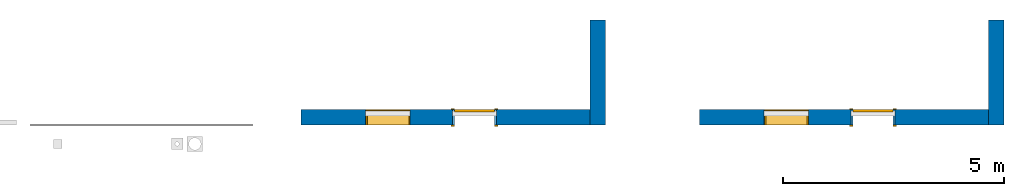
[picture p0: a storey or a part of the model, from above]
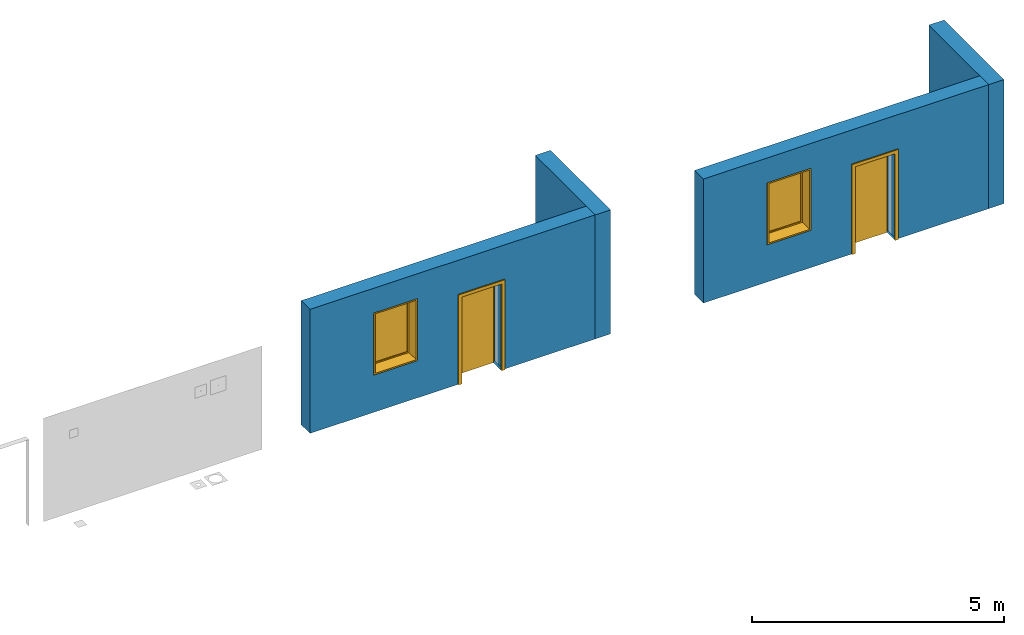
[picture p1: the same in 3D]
Properties of the parts of a building model (IFC2X3), part 1 of 2

# File
Description: ViewDefinition [CoordinationView_V2.0, QuantityTakeOffAddOnView]
File name: Project Number
Time: 2022-03-25T09:45:00
Written by: The EXPRESS Data Manager Version 5.02.0100.07 : 28 Aug 2013
Made in: 20200426_1515(x64) - Exporter 20.2.20.31 - Alternate UI 20.2.20.31
Comment: STEP Physical File produced by: The EXPRESS Data Manager Version 5.02.0100.07 : 28 Aug 2013 * Module: EDMstepFileFactory/EDMstandAlone * Creation date: Fri Mar 25 09:45:00 2022 * Host: DESKTOP-B61V6V9 * Database: C:\Users\3DBYGG~1\AppData\Local\Temp\b66c8e43-4149-422d-8c30-02023fbb521a\7cf2f51e-2db1-4240-b517-61d59570ed5c\ifc * Database version: 5507 * Database creation date: Fri Mar 25 09:44:56 2022 * Schema: IFC2X3 * Model: DataRepository.ifc * Model creation date: Fri Mar 25 09:44:57 2022 * Header model: DataRepository.ifc_HeaderModel * Header model creation date: Fri Mar 25 09:44:57 2022 * EDMuser: sdai-user * EDMgroup: sdai-group * License ID and type: 5605 : Permanent license. Expiry date: * EDMstepFileFactory options: 020000

# IfcProject, Project Number
LongName: Project Name; Phase: Project Status

# IfcSite, Default
RefLatitude: 42, 21, 31, 181945; RefLongitude: -71, -3, -24, -263305; RefElevation: 0 mm
Other - Category: Project Information; Client Name: Owner; Project Address: ## Street City, State Zip; Project Issue Date: Issue Date; Project Name: Project Name; Project Number: Project Number; Project Status: Project Status

# IfcBuilding
Pset_BuildingCommon - NumberOfStoreys: 1
Pset_ProductRequirements - Category: Project Information
Other - Category: Project Information; Client Name: Owner; Project Address: ## Street City, State Zip; Project Issue Date: Issue Date; Project Name: Project Name; Project Number: Project Number; Project Status: Project Status

# IfcBuildingStorey: Level:8mm Head, Level 1
LongName: Level 1; Elevation: 0 mm
Pset_AirSideSystemInformation - Name: Level 1
Pset_ProductRequirements - Name: Level 1; Category: Levels
Constraints - Elevation: 0 mm
Dimensions - Computation Height: 0 mm
Identity Data - Structural: no; Building Story: yes; Name: Level 1
Other - Category: Levels; Family: Level: 8mm Head; Family and Type: Level: 8mm Head; Type: Level: 8mm Head; Type Id: Level: 8mm Head
Constraints(Type) - Elevation Base: Project Base Point
Graphics(Type) - Color: 0; Line Pattern: Center; Line Weight: 1; Symbol: M_Level Head - Circle: M_Level Head - Circle; Symbol at End 1 Default: no; Symbol at End 2 Default: yes
Identity Data(Type) - Type Name: 8mm Head
Other(Type) - Category: Levels; Family Name: Level

# IfcBuildingElementProxy: Door Lining, Dafa_ExFoil_Lining_Foil 2 x double adhesive:Door Lining:279082
In: Level 1
Type - Material: DafaExFoilLiningFoil
Type - Constraints - Default Elevation: 0 mm
Type - Data - Foil Adhesive: DAFA foil adhesive; Vapor Barrier Tape: DAFA Hi-tack vapor barrier tape
Type - Dimensions - Thickness: 1 mm
Type - General - Revision: 1.0
Type - Green Building Properties - DGNB: Coming soon; EDP: Coming soon; EmiCode: Coming soon; Nordic Ecolabel: DAFA ExFoil lining foil is listed in the database for building products that can be used in Nordic Swan Ecolabelled buildings.
Type - Identity Data - Copyright: DAFA Building Solutions A/S; Description: With DAFA ExFoil lining foil, you are ensured an easy and secure installation of a vapor barrier at all 4 sides of openings/windows. This type of DAFA ExFoil lining foil is especially suitable for installation on new or existing vapor barriers, using two pre-installed sheets of double-sided tape.; Manufacturer: DAFA; Model: 250/410 mm x 50 m with 2 x double adhesive; Type Name: Door Lining; URL: https://DAFA-build.com/
Type - Other - Category: Generic Models; NominalWidth: 0 mm; AccessibilityPerformance: n/a; AssetIdentifier: n/a; AssetType: n/a; Author: DAFA Building Solutions A/S; BarCode: n/a; CodePerformance: n/a; Color: Transparent white w/ Lime green text; Constituents: n/a; DurationUnit: Year; ExpectedLife: n/a; Family Name: Dafa_ExFoil_Lining_Foil 2 x double adhesive; Features: Seals the opening all the way around, in one piece. DAFA ExFoil lining foil is fitted with butyl rubber and tape, which significantly facilitates the workflow; Finish: Nonwowen multilayer structure with reinforcing mesh; Grade: n/a; InstallationDate: To be filled by contractor; ManufacturerURL: https://DAFA-build.com; Material: Nonwowen multilayer structure with reinforcing mesh; ModelNumber: 620036876/620036582; ModelReference: DAFA AirStop System; NBSReference: n/a; NominalLength: 50000 mm; ProductInformation: https://DAFA-build.com/en/products/airstop/DAFA-exfoil-lining-foil; Reference: n/a; ReplacementCost: n/a; SerialNumber: n/a; Shape: Rectangular; Size: 250/410 mm x 50 m; TagNumber: n/a; WarrantyDescription: Depends on country.; WarrantyDurationLabor: To be filled by contractor; WarrantyDurationParts: Depends on country. Up to 30 years; WarrantyDurationUnit: Depends on country; WarrantyGuarantorLabor: To be filled by contractor; WarrantyGuarantorParts: To be filled by contractor; WarrantyStartDate: To be filled by contractor
Type - Pset_BuildingElementProxyCommon - Reference: n/a
Type - Pset_ElementShading - Color: Transparent white w/ Lime green text
Type - Pset_ManufacturerOccurrence - BarCode: n/a; SerialNumber: n/a
Type - Pset_ManufacturerTypeInformation - ModelReference: DAFA AirStop System; Manufacturer: DAFA
Type - Pset_PrecastConcreteElementGeneral - SerialNumber: n/a
Type - Pset_ProductRequirements - Category: Generic Models
Type - Pset_QuantityTakeOff - Reference: n/a
Pset_BuildingElementProxyCommon - sets with these values: 2
Constraints - Level: Level: Level 1; Elevation from Level: 0 mm; Moves With Nearby Elements: no; Offset from Host: 0 mm; Host: Level : Level 1
Dimensions - Area: 0.689456 m2; Depth: 120 mm; Height: 2100 mm; Volume: 0.00059376 m3; Width: 750 mm
Graphics - BottomOn: no
Materials and Finishes - ExFoilLining: DafaExFoilLiningFoil
Other - Family: Dafa_ExFoil_Lining_Foil 2 x double adhesive: Door Lining; Family and Type: Dafa_ExFoil_Lining_Foil 2 x double adhesive: Door Lining; Type: Dafa_ExFoil_Lining_Foil 2 x double adhesive: Door Lining; Type Id: Dafa_ExFoil_Lining_Foil 2 x double adhesive: Door Lining
Phasing - Phase Created: New Construction

# IfcBuildingElementProxy: Door Lining, Dafa_ExFoil_Lining_Foil double adhesive and butyl rubber:Door Lining:297118
In: Level 1
Type - Material: DafaExFoilLiningFoil
Type - Constraints - Default Elevation: 0 mm
Type - Data - Foil Adhesive: DAFA foil adhesive; Vapor Barrier Tape: DAFA Hi-tack vapor barrier tape
Type - Dimensions - Thickness: 1 mm
Type - General - Revision: 1.0
Type - Green Building Properties - DGNB: Coming soon; EDP: Coming soon; EmiCode: Coming soon; Nordic Ecolabel: DAFA ExFoil lining foil is listed in the database for building products that can be used in Nordic Swan Ecolabelled buildings.
Type - Identity Data - Copyright: DAFA Building Solutions A/S; Description: With DAFA ExFoil lining foil, you are ensured an easy and secure installation of a vapor barrier at all 4 sides of openings/windows. This type of DAFA ExFoil lining foil is preassembled with butyl rubber and tape, so that it works with rough surfaces such as concrete elements, aerated concrete and wood. Butyl rubber is extra strong and ensures good adhesion.; Manufacturer: DAFA; Model: 200/300/400 mm x 50 m with double adhesive and butyl; Type Name: Door Lining; URL: https://DAFA-build.com/
Type - Other - Category: Generic Models; NominalWidth: 0 mm; AccessibilityPerformance: n/a; AssetIdentifier: n/a; AssetType: n/a; Author: DAFA Building Solutions A/S; BarCode: n/a; CodePerformance: n/a; Color: Transparent white w/ Lime green text; Constituents: n/a; DurationUnit: Year; ExpectedLife: n/a; Family Name: Dafa_ExFoil_Lining_Foil double adhesive and butyl rubber; Features: Seals the opening all the way around, in one piece. DAFA ExFoil lining foil is fitted with butyl rubber and tape, which significantly facilitates the workflow; Finish: Nonwowen multilayer structure with reinforcing mesh; Grade: n/a; InstallationDate: To be filled by contractor; ManufacturerURL: https://DAFA-build.com; Material: Nonwowen multilayer structure with reinforcing mesh; ModelNumber: 620036874/620036875/620036584; ModelReference: DAFA AirStop System; NBSReference: n/a; NominalLength: 50000 mm; ProductInformation: https://DAFA-build.com/en/products/airstop/DAFA-exfoil-lining-foil; Reference: n/a; ReplacementCost: n/a; SerialNumber: n/a; Shape: Rectangular; Size: 200/300/400 mm x 50 m; TagNumber: n/a; WarrantyDescription: Depends on country.; WarrantyDurationLabor: To be filled by contractor; WarrantyDurationParts: Depends on country. Up to 30 years; WarrantyDurationUnit: Depends on country; WarrantyGuarantorLabor: To be filled by contractor; WarrantyGuarantorParts: To be filled by contractor; WarrantyStartDate: To be filled by contractor
Type - Pset_BuildingElementProxyCommon - Reference: n/a
Type - Pset_ElementShading - Color: Transparent white w/ Lime green text
Type - Pset_ManufacturerOccurrence - BarCode: n/a; SerialNumber: n/a
Type - Pset_ManufacturerTypeInformation - ModelReference: DAFA AirStop System; Manufacturer: DAFA
Type - Pset_PrecastConcreteElementGeneral - SerialNumber: n/a
Type - Pset_ProductRequirements - Category: Generic Models
Type - Pset_QuantityTakeOff - Reference: n/a
Pset_BuildingElementProxyCommon - sets with these values: 2
Constraints - Level: Level: Level 1; Elevation from Level: 0 mm; Moves With Nearby Elements: no; Offset from Host: 0 mm; Host: Level : Level 1
Dimensions - Area: 0.689456 m2; Depth: 120 mm; Height: 2100 mm; Volume: 0.00059376 m3; Width: 750 mm
Graphics - BottomOn: no
Materials and Finishes - ExFoilLining: DafaExFoilLiningFoil
Other - Family: Dafa_ExFoil_Lining_Foil double adhesive and butyl rubber: Door Lining; Family and Type: Dafa_ExFoil_Lining_Foil double adhesive and butyl rubber: Door Lining; Type: Dafa_ExFoil_Lining_Foil double adhesive and butyl rubber: Door Lining; Type Id: Dafa_ExFoil_Lining_Foil double adhesive and butyl rubber: Door Lining
Phasing - Phase Created: New Construction

# IfcBuildingElementProxy: Door Lining, Dafa_ExFoil_Lining_Foil 2 x double adhesive-WallBased:Door Lining:248374
In: Level 1
Type - Material: DafaExFoilLiningFoil
Type - Constraints(Type) - Default Elevation: 0 mm
Type - Data(Type) - Foil Adhesive: DAFA foil adhesive; Vapor Barrier Tape: DAFA Hi-tack vapor barrier tape
Type - Dimensions(Type) - Area: 0.624 m2; Depth: 120 mm; Height: 2100 mm; Width: 1000 mm
Type - General(Type) - Revision: 1.0
Type - Graphics(Type) - BottomOn: no
Type - Green Building Properties(Type) - DGNB: Coming soon; EDP: Coming soon; EmiCode: Coming soon; Nordic Ecolabel: DAFA ExFoil lining foil is listed in the database for building products that can be used in Nordic Swan Ecolabelled buildings.
Type - Identity Data(Type) - Copyright: DAFA Building Solutions A/S; Description: With DAFA ExFoil lining foil, you are ensured an easy and secure installation of a vapor barrier at all 4 sides of openings/windows. This type of DAFA ExFoil lining foil is especially suitable for installation on new or existing vapor barriers, using two pre-installed sheets of double-sided tape.; Manufacturer: DAFA; Model: 250/410 mm x 50 m with 2 x double adhesive; Type Name: Door Lining; URL: https://DAFA-build.com/
Type - Other(Type) - Category: Generic Models; NominalWidth: 0 mm; AccessibilityPerformance: n/a; AssetIdentifier: n/a; AssetType: n/a; Author: DAFA Building Solutions A/S; BarCode: n/a; CodePerformance: n/a; Color: Transparent white w/ Lime green text; Constituents: n/a; DurationUnit: Year; ExpectedLife: n/a; Family Name: Dafa_ExFoil_Lining_Foil 2 x double adhesive-WallBased; Features: Seals the opening all the way around, in one piece. DAFA ExFoil lining foil is fitted with butyl rubber and tape, which significantly facilitates the workflow; Finish: Nonwowen multilayer structure with reinforcing mesh; Grade: n/a; InstallationDate: To be filled by contractor; ManufacturerURL: https://DAFA-build.com; Material: Nonwowen multilayer structure with reinforcing mesh; ModelNumber: 620036876/620036582; ModelReference: DAFA AirStop System; NBSReference: n/a; NominalLength: 50000 mm; ProductInformation: https://DAFA-build.com/en/products/airstop/DAFA-exfoil-lining-foil; Reference: n/a; ReplacementCost: n/a; SerialNumber: n/a; Shape: Rectangular; Size: 250/410 mm x 50 m; TagNumber: n/a; WarrantyDescription: Depends on country.; WarrantyDurationLabor: To be filled by contractor; WarrantyDurationParts: Depends on country. Up to 30 years; WarrantyDurationUnit: Depends on country; WarrantyGuarantorLabor: To be filled by contractor; WarrantyGuarantorParts: To be filled by contractor; WarrantyStartDate: To be filled by contractor
Type - Pset_BuildingElementProxyCommon - Reference: n/a
Type - Pset_ElementShading - Color: Transparent white w/ Lime green text
Type - Pset_ManufacturerOccurrence - BarCode: n/a; SerialNumber: n/a
Type - Pset_ManufacturerTypeInformation - ModelReference: DAFA AirStop System; Manufacturer: DAFA
Type - Pset_PrecastConcreteElementGeneral - SerialNumber: n/a
Type - Pset_ProductRequirements - Category: Generic Models
Type - Pset_QuantityTakeOff - Reference: n/a
Pset_BuildingElementProxyCommon - sets with these values: 2
Constraints - Level: Level: Level 1; Elevation from Level: 0.708015 mm
Dimensions - Area: 0.749956 m2; OffsetInWall: 25 mm; Volume: 0.00062376 m3
Other - Category: Generic Models; Host Id: Basic Wall: Exterior - Brick on Mtl. Stud; Family: Dafa_ExFoil_Lining_Foil 2 x double adhesive-WallBased: Door Lining; Family and Type: Dafa_ExFoil_Lining_Foil 2 x double adhesive-WallBased: Door Lining; Type: Dafa_ExFoil_Lining_Foil 2 x double adhesive-WallBased: Door Lining; Type Id: Dafa_ExFoil_Lining_Foil 2 x double adhesive-WallBased: Door Lining
Phasing - Phase Created: New Construction

# IfcBuildingElementProxy: Door Lining, Dafa_ExFoil_Lining_Foil double adhesive and butyl rubber-WallBased:Door Lining:297191
In: Level 1
Type - Material: DafaExFoilLiningFoil
Type - Constraints(Type) - Default Elevation: 0 mm
Type - Data(Type) - Foil Adhesive: DAFA foil adhesive; Vapor Barrier Tape: DAFA Hi-tack vapor barrier tape
Type - Dimensions(Type) - Area: 0.624 m2; Depth: 120 mm; Height: 2100 mm; Width: 1000 mm
Type - General(Type) - Revision: 1.0
Type - Graphics(Type) - BottomOn: no
Type - Green Building Properties(Type) - DGNB: Coming soon; EDP: Coming soon; EmiCode: Coming soon; Nordic Ecolabel: DAFA ExFoil lining foil is listed in the database for building products that can be used in Nordic Swan Ecolabelled buildings.
Type - Identity Data(Type) - Copyright: DAFA Building Solutions A/S; Description: With DAFA ExFoil lining foil, you are ensured an easy and secure installation of a vapor barrier at all 4 sides of openings/windows. This type of DAFA ExFoil lining foil is preassembled with butyl rubber and tape, so that it works with rough surfaces such as concrete elements, aerated concrete and wood. Butyl rubber is extra strong and ensures good adhesion.; Manufacturer: DAFA; Model: 200/300/400 mm x 50 m with double adhesive and butyl; Type Name: Door Lining; URL: https://DAFA-build.com/
Type - Other(Type) - Category: Generic Models; NominalWidth: 0 mm; AccessibilityPerformance: n/a; AssetIdentifier: n/a; AssetType: n/a; Author: DAFA Building Solutions A/S; BarCode: n/a; CodePerformance: n/a; Color: Transparent white w/ Lime green text; Constituents: n/a; DurationUnit: Year; ExpectedLife: n/a; Family Name: Dafa_ExFoil_Lining_Foil double adhesive and butyl rubber-WallBased; Features: Seals the opening all the way around, in one piece. DAFA ExFoil lining foil is fitted with butyl rubber and tape, which significantly facilitates the workflow; Finish: Nonwowen multilayer structure with reinforcing mesh; Grade: n/a; InstallationDate: To be filled by contractor; ManufacturerURL: https://DAFA-build.com; Material: Nonwowen multilayer structure with reinforcing mesh; ModelNumber: 620036874/620036875/620036584; ModelReference: DAFA AirStop System; NBSReference: n/a; NominalLength: 50000 mm; ProductInformation: https://DAFA-build.com/en/products/airstop/DAFA-exfoil-lining-foil; Reference: n/a; ReplacementCost: n/a; SerialNumber: n/a; Shape: Rectangular; Size: 200/300/400 mm x 50 m; TagNumber: n/a; WarrantyDescription: Depends on country.; WarrantyDurationLabor: To be filled by contractor; WarrantyDurationParts: Depends on country. Up to 30 years; WarrantyDurationUnit: Depends on country; WarrantyGuarantorLabor: To be filled by contractor; WarrantyGuarantorParts: To be filled by contractor; WarrantyStartDate: To be filled by contractor
Type - Pset_BuildingElementProxyCommon - Reference: n/a
Type - Pset_ElementShading - Color: Transparent white w/ Lime green text
Type - Pset_ManufacturerOccurrence - BarCode: n/a; SerialNumber: n/a
Type - Pset_ManufacturerTypeInformation - ModelReference: DAFA AirStop System; Manufacturer: DAFA
Type - Pset_PrecastConcreteElementGeneral - SerialNumber: n/a
Type - Pset_ProductRequirements - Category: Generic Models
Type - Pset_QuantityTakeOff - Reference: n/a
Pset_BuildingElementProxyCommon - sets with these values: 2
Constraints - Level: Level: Level 1; Elevation from Level: 0.708015 mm
Dimensions - Area: 0.749956 m2; OffsetInWall: 25 mm; Volume: 0.00062376 m3
Other - Category: Generic Models; Host Id: Basic Wall: Exterior - Brick on Mtl. Stud; Family: Dafa_ExFoil_Lining_Foil double adhesive and butyl rubber-WallBased: Door Lining; Family and Type: Dafa_ExFoil_Lining_Foil double adhesive and butyl rubber-WallBased: Door Lining; Type: Dafa_ExFoil_Lining_Foil double adhesive and butyl rubber-WallBased: Door Lining; Type Id: Dafa_ExFoil_Lining_Foil double adhesive and butyl rubber-WallBased: Door Lining
Phasing - Phase Created: New Construction

# IfcBuildingElementProxy: Standard, Dafa_ExFoil:Standard:239079
In: Level 1
Type - Material: DafaExFoil
Type - Constraints - Default Elevation: 0 mm
Type - Data - Foil Adhesive: DAFA foil adhesive; Vapor Barrier Tape: DAFA Hi-tack vapor barrier tape
Type - General - Revision: 1.0
Type - Green Building Properties - DGNB: Coming soon; EDP: Coming soon; EmiCode: Coming soon; Nordic Ecolabel: DAFA ExFoil is listed in the database for building products that can be used in Nordic Swan Ecolabelled buildings.
Type - Identity Data - Copyright: DAFA Building Solutions A/S; Description: DAFA ExFoil vapor barrier foil is an extra strong foil vapor barrier with reinforcing mesh and a multilayer structure which makes it extremely stretch and tear-resistant.; Manufacturer: DAFA; Model: ExFoil; Type Name: Standard; URL: https://DAFA-build.com/
Type - Other - Category: Generic Models; NominalWidth: 0 mm; AccessibilityPerformance: n/a; AssetIdentifier: n/a; AssetType: n/a; Author: DAFA Building Solutions A/S; BarCode: n/a; CodePerformance: n/a; Color: Transparent white w/ Lime green text; Constituents: n/a; DurationUnit: Year; ExpectedLife: n/a; Family Name: Dafa_ExFoil; Features: Far more construction-friendly than a standard PE vapor barrier, making installation easier. With reinforcing mesh, DAFA ExFoil is much stronger than a PE vapor barrier; Finish: Multilayer structure with mesh reinforcement; Grade: n/a; InstallationDate: To be filled by contractor; ManufacturerURL: https://DAFA-build.com; Material: Nonwowen multilayer structure with reinforcing mesh; ModelNumber: 620035141 / 620038158; ModelReference: DAFA AirStop System; NBSReference: n/a; NominalLength: 0 mm; ProductInformation: https://dafa-build.com/en/products/airstop/exfoil; Reference: n/a; ReplacementCost: n/a; SerialNumber: n/a; Shape: Rectangular/roll; Size: 2,15 x 46, 5 m / 2,7 x 37 m; TagNumber: n/a; WarrantyDescription: Depends on country.; WarrantyDurationLabor: To be filled by contractor; WarrantyDurationParts: Depends on country. 30 years; WarrantyDurationUnit: Depends on country; WarrantyGuarantorLabor: To be filled by contractor; WarrantyGuarantorParts: To be filled by contractor; WarrantyStartDate: To be filled by contractor
Type - Pset_BuildingElementProxyCommon - Reference: n/a
Type - Pset_ElementShading - Color: Transparent white w/ Lime green text
Type - Pset_ManufacturerOccurrence - BarCode: n/a; SerialNumber: n/a
Type - Pset_ManufacturerTypeInformation - ModelReference: DAFA AirStop System; Manufacturer: DAFA
Type - Pset_PrecastConcreteElementGeneral - SerialNumber: n/a
Type - Pset_ProductRequirements - Category: Generic Models
Type - Pset_QuantityTakeOff - Reference: n/a
Pset_BuildingElementProxyCommon - sets with these values: 2
Constraints - Level: Level: Level 1; Elevation from Level: 0 mm; Host: Level : Level 1; Moves With Nearby Elements: no; Offset from Host: 0 mm
Dimensions - Area: 12.5075 m2; Height: 2500 mm; Thickness: 1 mm; Volume: 0.0125 m3; Width: 5000 mm
Materials and Finishes - ExFoil: DafaExFoil
Other - Family: Dafa_ExFoil: Standard; Family and Type: Dafa_ExFoil: Standard; Type: Dafa_ExFoil: Standard; Type Id: Dafa_ExFoil: Standard
Phasing - Phase Created: New Construction

# IfcBuildingElementProxy: Type 195, Dafa_Hi-tack_Cable_Collar:Type 195:256911
In: Level 1
Type - Material: DAFA Hitack
Type - Constraints - Default Elevation: 0 mm
Type - General - Revision: 1.0
Type - Green Building Properties - DGNB: Coming soon; EDP: Coming soon; EmiCode: Coming soon; Nordic Ecolabel: DAFA Hi-tack cable collar is listed in the database for building products that can be used in Nordic Swan Ecolabelled buildings
Type - Identity Data - Copyright: DAFA Building Solutions A/S; Description: DAFA Hi-tack universal cable collars are a patented solution used for sealing the vapor barrier around cable and ceiling outlet penetrations. Attach the collar directly to the vapor barrier – quickly, simply and securely. A single flexible gasket for all common pipe dimensions/exhaust ducts; Manufacturer: DAFA; Model: Type 195; Type Name: Type 195; URL: https://DAFA-build.com/
Type - Other - Category: Generic Models; AccessibilityPerformance: n/a; AssetIdentifier: n/a; AssetType: n/a; Author: DAFA Building Solutions A/S; BarCode: n/a; CodePerformance: n/a; Color: Black; Constituents: n/a; DurationUnit: Year; ExpectedLife: n/a; Family Name: Dafa_Hi-tack_Cable_Collar; Features: A single flexible gasket for all common cable dimensions.Can be used for both cables and ceiling outlets (PL junction boxes with rubber plugs). Simple, fast and secure installation. No special tools required. Installed without the need for subsequent sealing, gluing, caulking, etc.; Finish: The product is made from a black, soft and flexible EPDM fabric, coated with a strong acrylic adhesive. The adhesive has been specially developed for sealing and laminating a DAFA HiFoil and ExFoil vapour barriers. The 1.2 mm thick EPDM fabric is supplied with pre-punched markings.; Grade: n/a; InstallationDate: To be filled by contractor; ManufacturerURL: https://DAFA-build.com; Material: EPDM; ModelNumber: 620026738; ModelReference: DAFA AirStop System; NBSReference: n/a; NominalLength: 195 mm; NominalWidth: 195 mm; ProductInformation: https://dafa-build.com/en/products/airstop/dafa-hi-tack-universal-cable-collar; Reference: n/a; ReplacementCost: n/a; SerialNumber: n/a; Shape: Rectangular; Size: 195 x 195 mm; TagNumber: n/a; WarrantyDescription: Depends on country.; WarrantyDurationLabor: To be filled by contractor; WarrantyDurationParts: Depends on country. Up to 30 years; WarrantyDurationUnit: Depends on country; WarrantyGuarantorLabor: To be filled by contractor; WarrantyGuarantorParts: To be filled by contractor; WarrantyStartDate: To be filled by contractor
Type - Pset_BuildingElementProxyCommon - Reference: n/a
Type - Pset_ElementShading - Color: Black
Type - Pset_ManufacturerOccurrence - BarCode: n/a; SerialNumber: n/a
Type - Pset_ManufacturerTypeInformation - ModelReference: DAFA AirStop System; Manufacturer: DAFA
Type - Pset_PrecastConcreteElementGeneral - SerialNumber: n/a
Type - Pset_ProductRequirements - Category: Generic Models
Type - Pset_QuantityTakeOff - Reference: n/a
Pset_BuildingElementProxyCommon - sets with these values: 2
Constraints - Level: Level: Level 1; Elevation from Level: 0 mm; Moves With Nearby Elements: no; Offset from Host: 0 mm; Host: Level : Level 1
Dimensions - Area: 0.038493 m2; Volume: 0.00004563 m3; Width: 195 mm
Materials and Finishes - Collar: DAFA Collar; Hitack: DAFA Hitack
Other - Family: Dafa_Hi-tack_Cable_Collar: Type 195; Family and Type: Dafa_Hi-tack_Cable_Collar: Type 195; Type: Dafa_Hi-tack_Cable_Collar: Type 195; Type Id: Dafa_Hi-tack_Cable_Collar: Type 195
Phasing - Phase Created: New Construction

# IfcBuildingElementProxy: Type 195, Dafa_Hi-tack_Cable_Collar_FaceBased:Type 195:278831
In: Level 1
Type - Material: DAFA Hitack
Type - Constraints - Default Elevation: 1219.2 mm
Type - Dimensions - Width: 195 mm
Type - General - Revision: 1.0
Type - Green Building Properties - DGNB: Coming soon; EDP: Coming soon; EmiCode: Coming soon; Nordic Ecolabel: DAFA Hi-tack cable collar is listed in the database for building products that can be used in Nordic Swan Ecolabelled buildings
Type - Identity Data - Copyright: DAFA Building Solutions A/S; Description: DAFA Hi-tack universal cable collars are a patented solution used for sealing the vapor barrier around cable and ceiling outlet penetrations. Attach the collar directly to the vapor barrier – quickly, simply and securely. A single flexible gasket for all common pipe dimensions/exhaust ducts; Manufacturer: DAFA; Model: Type 195; Type Name: Type 195; URL: https://DAFA-build.com/
Type - Materials and Finishes - Hitack: DAFA Hitack
Type - Other - Category: Generic Models; AccessibilityPerformance: n/a; AssetIdentifier: n/a; AssetType: n/a; Author: DAFA Building Solutions A/S; BarCode: n/a; CodePerformance: n/a; Color: Black; Constituents: n/a; DurationUnit: Year; ExpectedLife: n/a; Family Name: Dafa_Hi-tack_Cable_Collar_FaceBased; Features: A single flexible gasket for all common cable dimensions.Can be used for both cables and ceiling outlets (PL junction boxes with rubber plugs). Simple, fast and secure installation. No special tools required. Installed without the need for subsequent sealing, gluing, caulking, etc.; Finish: The product is made from a black, soft and flexible EPDM fabric, coated with a strong acrylic adhesive. The adhesive has been specially developed for sealing and laminating a DAFA HiFoil and ExFoil vapour barriers. The 1.2 mm thick EPDM fabric is supplied with pre-punched markings.; Grade: n/a; InstallationDate: To be filled by contractor; ManufacturerURL: https://DAFA-build.com; Material: EPDM; ModelNumber: 620026738; ModelReference: DAFA AirStop System; NBSReference: n/a; NominalLength: 195 mm; NominalWidth: 195 mm; ProductInformation: https://dafa-build.com/en/products/airstop/dafa-hi-tack-universal-cable-collar; Reference: n/a; ReplacementCost: n/a; SerialNumber: n/a; Shape: Rectangular; Size: 195 x 195 mm; TagNumber: n/a; WarrantyDescription: Depends on country.; WarrantyDurationLabor: To be filled by contractor; WarrantyDurationParts: Depends on country. Up to 30 years; WarrantyDurationUnit: Depends on country; WarrantyGuarantorLabor: To be filled by contractor; WarrantyGuarantorParts: To be filled by contractor; WarrantyStartDate: To be filled by contractor
Type - Pset_BuildingElementProxyCommon - Reference: n/a
Type - Pset_ElementShading - Color: Black
Type - Pset_ManufacturerOccurrence - BarCode: n/a; SerialNumber: n/a
Type - Pset_ManufacturerTypeInformation - ModelReference: DAFA AirStop System; Manufacturer: DAFA
Type - Pset_PrecastConcreteElementGeneral - SerialNumber: n/a
Type - Pset_ProductRequirements - Category: Generic Models
Type - Pset_QuantityTakeOff - Reference: n/a
Pset_BuildingElementProxyCommon - sets with these values: 2
Constraints - Level: Level: Level 1; Schedule Level: Level: Level 1; Elevation from Level: 1900 mm; Host: Dafa_ExFoil : Standard
Dimensions - Area: 0.038493 m2; Volume: 0.00004563 m3
Materials and Finishes - Collar: DAFA Collar
Other - Family: Dafa_Hi-tack_Cable_Collar_FaceBased: Type 195; Family and Type: Dafa_Hi-tack_Cable_Collar_FaceBased: Type 195; Type: Dafa_Hi-tack_Cable_Collar_FaceBased: Type 195; Type Id: Dafa_Hi-tack_Cable_Collar_FaceBased: Type 195
Phasing - Phase Created: New Construction

# IfcBuildingElementProxy: Type 260, Dafa_Hi-tack_Pipe_Collar:Type 260:253812
In: Level 1
Type - Material: DAFA Hitack
Type - Constraints - Default Elevation: 0 mm
Type - Construction - HoleType: 1
Type - Dimensions - Width: 260 mm
Type - General - Revision: 1.0; Type 260: yes; Type 345: no
Type - Graphics - FilledHole: no
Type - Green Building Properties - DGNB: Coming soon; EDP: Coming soon; EmiCode: Coming soon; Nordic Ecolabel: The DAFA Hi-tack pipe collar is included in the Nordic Ecolabellings database of construction products that can be used in Swan-labelled buildings.
Type - Identity Data - Copyright: DAFA Building Solutions A/S; Description: DAFA Hi-tack universal pipe collars are a patented solution used for sealing the vapor barrier around pipe penetrations. Attach the collar directly to the vapor barrier – quickly, simply and securely.; Manufacturer: DAFA; Model: Type 260; Type Name: Type 260; URL: https://DAFA-build.com/
Type - Other - Category: Generic Models; AccessibilityPerformance: n/a; AssetIdentifier: n/a; AssetType: n/a; Author: DAFA Building Solutions A/S; BarCode: n/a; CodePerformance: n/a; Color: Black; Constituents: n/a; DurationUnit: Year; ExpectedLife: n/a; Family Name: Dafa_Hi-tack_Pipe_Collar; Features: A single flexible seal suitable for all common pipe dimensions/ventilations shafts (but not flexible pipe). Simple, fast and secure installation. No special tools required. Installed without the need for subsequent sealing, gluing, caulking, etc.; Finish: The product is made from a black, soft and flexible EPDM fabric, coated with a strong acrylic adhesive. The adhesive has been specially developed for sealing and laminating a DAFA HiFoil and ExFoil vapour barriers. The 1.2 mm thick EPDM fabric is supplied with pre-punched markings.; Grade: n/a; InstallationDate: To be filled by contractor; ManufacturerURL: https://DAFA-build.com; Material: EPDM; ModelNumber: 620026737; ModelReference: DAFA AirStop System; NBSReference: n/a; NominalLength: 260 mm; NominalWidth: 260 mm; ProductInformation: https://dafa-build.com/en/products/airstop/dafa-hi-tack-pipe-collar; Reference: n/a; ReplacementCost: n/a; SerialNumber: n/a; Shape: Rectangular; Size: 260 x 260 mm; TagNumber: n/a; WarrantyDescription: Depends on country.; WarrantyDurationLabor: To be filled by contractor; WarrantyDurationParts: Depends on country. Up to 30 years; WarrantyDurationUnit: Depends on country; WarrantyGuarantorLabor: To be filled by contractor; WarrantyGuarantorParts: To be filled by contractor; WarrantyStartDate: To be filled by contractor
Type - Pset_BuildingElementProxyCommon - Reference: n/a
Type - Pset_ElementShading - Color: Black
Type - Pset_ManufacturerOccurrence - BarCode: n/a; SerialNumber: n/a
Type - Pset_ManufacturerTypeInformation - ModelReference: DAFA AirStop System; Manufacturer: DAFA
Type - Pset_PrecastConcreteElementGeneral - SerialNumber: n/a
Type - Pset_ProductRequirements - Category: Generic Models
Type - Pset_QuantityTakeOff - Reference: n/a
Pset_BuildingElementProxyCommon - sets with these values: 2
Constraints - Level: Level: Level 1; Elevation from Level: 0 mm; Moves With Nearby Elements: no; Offset from Host: 0 mm; Host: Level : Level 1
Construction - Circle: 3
Dimensions - Area: 0.0685633 m2; Radius: 45 mm; Volume: 0.0000734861 m3
General - 100mmCircle: no; 12mmCircle: no; 135mmCircle: no; 25mmCircle: no; 45mmCircle: yes; 55mmCircle: no; 60mmCircle: no; 70mmCircle: no; CableCollar: no
Materials and Finishes - Collar: DAFA Collar; Hitack: DAFA Hitack
Other - Family: Dafa_Hi-tack_Pipe_Collar: Type 260; Family and Type: Dafa_Hi-tack_Pipe_Collar: Type 260; Type: Dafa_Hi-tack_Pipe_Collar: Type 260; Type Id: Dafa_Hi-tack_Pipe_Collar: Type 260
Phasing - Phase Created: New Construction

# IfcBuildingElementProxy: Type 260, Dafa_Hi-tack_Pipe_Collar_FaceBased:Type 260:277890
In: Level 1
Type - Material: DAFA Hitack
Type - Constraints - Default Elevation: 1219.2 mm
Type - Construction - HoleType: 1
Type - Data - Circle: 3
Type - General - Revision: 1.0
Type - Graphics - FilledHole: no
Type - Green Building Properties - DGNB: Coming soon; EDP: Coming soon; EmiCode: Coming soon; Nordic Ecolabel: The DAFA Hi-tack pipe collar is included in the Nordic Ecolabellings database of construction products that can be used in Swan-labelled buildings.
Type - Identity Data - Copyright: DAFA Building Solutions A/S; Description: DAFA Hi-tack universal pipe collars are a patented solution used for sealing the vapor barrier around pipe penetrations. Attach the collar directly to the vapor barrier – quickly, simply and securely.; Manufacturer: DAFA; Model: Type 260; Type Name: Type 260; URL: https://DAFA-build.com/
Type - Materials and Finishes - Collar: DAFA Collar; Hitack: DAFA Hitack
Type - Other - Category: Generic Models; AccessibilityPerformance: n/a; AssetIdentifier: n/a; AssetType: n/a; Author: DAFA Building Solutions A/S; BarCode: n/a; CodePerformance: n/a; Color: Black; Constituents: n/a; DurationUnit: Year; ExpectedLife: n/a; Family Name: Dafa_Hi-tack_Pipe_Collar_FaceBased; Features: A single flexible seal suitable for all common pipe dimensions/ventilations shafts (but not flexible pipe). Simple, fast and secure installation. No special tools required. Installed without the need for subsequent sealing, gluing, caulking, etc.; Finish: The product is made from a black, soft and flexible EPDM fabric, coated with a strong acrylic adhesive. The adhesive has been specially developed for sealing and laminating a DAFA HiFoil and ExFoil vapour barriers. The 1.2 mm thick EPDM fabric is supplied with pre-punched markings.; Grade: n/a; InstallationDate: To be filled by contractor; ManufacturerURL: https://DAFA-build.com; Material: EPDM; ModelNumber: 620026737; ModelReference: DAFA AirStop System; NBSReference: n/a; NominalLength: 260 mm; NominalWidth: 260 mm; ProductInformation: https://dafa-build.com/en/products/airstop/dafa-hi-tack-pipe-collar; Reference: n/a; ReplacementCost: n/a; SerialNumber: n/a; Shape: Rectangular; Size: 260 x 260 mm; TagNumber: n/a; WarrantyDescription: Depends on country.; WarrantyDurationLabor: To be filled by contractor; WarrantyDurationParts: Depends on country. Up to 30 years; WarrantyDurationUnit: Depends on country; WarrantyGuarantorLabor: To be filled by contractor; WarrantyGuarantorParts: To be filled by contractor; WarrantyStartDate: To be filled by contractor
Type - Pset_BuildingElementProxyCommon - Reference: n/a
Type - Pset_ElementShading - Color: Black
Type - Pset_ManufacturerOccurrence - BarCode: n/a; SerialNumber: n/a
Type - Pset_ManufacturerTypeInformation - ModelReference: DAFA AirStop System; Manufacturer: DAFA
Type - Pset_PrecastConcreteElementGeneral - SerialNumber: n/a
Type - Pset_ProductRequirements - Category: Generic Models
Type - Pset_QuantityTakeOff - Reference: n/a
Pset_BuildingElementProxyCommon - sets with these values: 2
Constraints - Level: Level: Level 1; Elevation from Level: 1900 mm; Host: Dafa_ExFoil : Standard; Schedule Level: Level: Level 1
Dimensions - Area: 0.0682994 m2; Volume: 0.000080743 m3
Other - Family: Dafa_Hi-tack_Pipe_Collar_FaceBased: Type 260; Family and Type: Dafa_Hi-tack_Pipe_Collar_FaceBased: Type 260; Type: Dafa_Hi-tack_Pipe_Collar_FaceBased: Type 260; Type Id: Dafa_Hi-tack_Pipe_Collar_FaceBased: Type 260
Phasing - Phase Created: New Construction

# IfcBuildingElementProxy: Type 345, Dafa_Hi-tack_Pipe_Collar:Type 345:254169
In: Level 1
Type - Material: DAFA Hitack
Type - Constraints - Default Elevation: 0 mm
Type - Construction - HoleType: 2
Type - Dimensions - Width: 345 mm
Type - General - Revision: 1.0; Type 260: no; Type 345: yes
Type - Graphics - FilledHole: no
Type - Green Building Properties - DGNB: Coming soon; EDP: Coming soon; EmiCode: Coming soon; Nordic Ecolabel: The DAFA Hi-tack pipe collar is included in the Nordic Ecolabellings database of construction products that can be used in Swan-labelled buildings.
Type - Identity Data - Copyright: DAFA Building Solutions A/S; Description: DAFA Hi-tack universal pipe collars are a patented solution used for sealing the vapor barrier around pipe penetrations. Attach the collar directly to the vapor barrier – quickly, simply and securely.; Manufacturer: DAFA; Model: Type 345; Type Name: Type 345; URL: https://DAFA-build.com/
Type - Other - Category: Generic Models; AccessibilityPerformance: n/a; AssetIdentifier: n/a; AssetType: n/a; Author: DAFA Building Solutions A/S; BarCode: n/a; CodePerformance: n/a; Color: Black; Constituents: n/a; DurationUnit: Year; ExpectedLife: n/a; Family Name: Dafa_Hi-tack_Pipe_Collar; Features: A single flexible seal suitable for all common pipe dimensions/ventilations shafts (but not flexible pipe). Simple, fast and secure installation. No special tools required. Installed without the need for subsequent sealing, gluing, caulking, etc.; Finish: The product is made from a black, soft and flexible EPDM fabric, coated with a strong acrylic adhesive. The adhesive has been specially developed for sealing and laminating a DAFA HiFoil and ExFoil vapour barriers. The 1.2 mm thick EPDM fabric is supplied with pre-punched markings.; Grade: n/a; InstallationDate: To be filled by contractor; ManufacturerURL: https://DAFA-build.com; Material: EPDM; ModelNumber: 620027032; ModelReference: DAFA AirStop System; NBSReference: n/a; NominalLength: 345 mm; NominalWidth: 345 mm; ProductInformation: https://dafa-build.com/en/products/airstop/dafa-hi-tack-pipe-collar; Reference: n/a; ReplacementCost: n/a; SerialNumber: n/a; Shape: Rectangular; Size: 345 x 345 mm; TagNumber: n/a; WarrantyDescription: Depends on country.; WarrantyDurationLabor: To be filled by contractor; WarrantyDurationParts: Depends on country. Up to 30 years; WarrantyDurationUnit: Depends on country; WarrantyGuarantorLabor: To be filled by contractor; WarrantyGuarantorParts: To be filled by contractor; WarrantyStartDate: To be filled by contractor
Type - Pset_BuildingElementProxyCommon - Reference: n/a
Type - Pset_ElementShading - Color: Black
Type - Pset_ManufacturerOccurrence - BarCode: n/a; SerialNumber: n/a
Type - Pset_ManufacturerTypeInformation - ModelReference: DAFA AirStop System; Manufacturer: DAFA
Type - Pset_PrecastConcreteElementGeneral - SerialNumber: n/a
Type - Pset_ProductRequirements - Category: Generic Models
Type - Pset_QuantityTakeOff - Reference: n/a
Pset_BuildingElementProxyCommon - sets with these values: 2
Constraints - Level: Level: Level 1; Elevation from Level: 0 mm; Moves With Nearby Elements: no; Offset from Host: 0 mm; Host: Level : Level 1
Construction - Circle: 3
Dimensions - Area: 0.120871 m2; Radius: 135 mm; Volume: 0.0000741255 m3
General - 100mmCircle: no; 12mmCircle: no; 25mmCircle: no; 55mmCircle: no; 60mmCircle: no; 70mmCircle: no; CableCollar: no; 135mmCircle: yes; 45mmCircle: no
Materials and Finishes - Collar: DAFA Collar; Hitack: DAFA Hitack
Other - Family: Dafa_Hi-tack_Pipe_Collar: Type 345; Family and Type: Dafa_Hi-tack_Pipe_Collar: Type 345; Type: Dafa_Hi-tack_Pipe_Collar: Type 345; Type Id: Dafa_Hi-tack_Pipe_Collar: Type 345
Phasing - Phase Created: New Construction

# IfcBuildingElementProxy: Type 345, Dafa_Hi-tack_Pipe_Collar_FaceBased:Type 345:278053
In: Level 1
Type - Material: DAFA Hitack
Type - Constraints - Default Elevation: 1219.2 mm
Type - Construction - HoleType: 2
Type - Data - Circle: 3
Type - General - Revision: 1.0
Type - Graphics - FilledHole: no
Type - Green Building Properties - DGNB: Coming soon; EDP: Coming soon; EmiCode: Coming soon; Nordic Ecolabel: The DAFA Hi-tack pipe collar is included in the Nordic Ecolabellings database of construction products that can be used in Swan-labelled buildings.
Type - Identity Data - Copyright: DAFA Building Solutions A/S; Description: DAFA Hi-tack universal pipe collars are a patented solution used for sealing the vapor barrier around pipe penetrations. Attach the collar directly to the vapor barrier – quickly, simply and securely.; Manufacturer: DAFA; Model: Type 345; Type Name: Type 345; URL: https://DAFA-build.com/
Type - Materials and Finishes - Collar: DAFA Collar; Hitack: DAFA Hitack
Type - Other - Category: Generic Models; AccessibilityPerformance: n/a; AssetIdentifier: n/a; AssetType: n/a; Author: DAFA Building Solutions A/S; BarCode: n/a; CodePerformance: n/a; Color: Black; Constituents: n/a; DurationUnit: Year; ExpectedLife: n/a; Family Name: Dafa_Hi-tack_Pipe_Collar_FaceBased; Features: A single flexible seal suitable for all common pipe dimensions/ventilations shafts (but not flexible pipe). Simple, fast and secure installation. No special tools required. Installed without the need for subsequent sealing, gluing, caulking, etc.; Finish: The product is made from a black, soft and flexible EPDM fabric, coated with a strong acrylic adhesive. The adhesive has been specially developed for sealing and laminating a DAFA HiFoil and ExFoil vapour barriers. The 1.2 mm thick EPDM fabric is supplied with pre-punched markings.; Grade: n/a; InstallationDate: To be filled by contractor; ManufacturerURL: https://DAFA-build.com; Material: EPDM; ModelNumber: 620027032; ModelReference: DAFA AirStop System; NBSReference: n/a; NominalLength: 345 mm; NominalWidth: 345 mm; ProductInformation: https://dafa-build.com/en/products/airstop/dafa-hi-tack-pipe-collar; Reference: n/a; ReplacementCost: n/a; SerialNumber: n/a; Shape: Rectangular; Size: 345 x 345 mm; TagNumber: n/a; WarrantyDescription: Depends on country.; WarrantyDurationLabor: To be filled by contractor; WarrantyDurationParts: Depends on country. Up to 30 years; WarrantyDurationUnit: Depends on country; WarrantyGuarantorLabor: To be filled by contractor; WarrantyGuarantorParts: To be filled by contractor; WarrantyStartDate: To be filled by contractor
Type - Pset_BuildingElementProxyCommon - Reference: n/a
Type - Pset_ElementShading - Color: Black
Type - Pset_ManufacturerOccurrence - BarCode: n/a; SerialNumber: n/a
Type - Pset_ManufacturerTypeInformation - ModelReference: DAFA AirStop System; Manufacturer: DAFA
Type - Pset_PrecastConcreteElementGeneral - SerialNumber: n/a
Type - Pset_ProductRequirements - Category: Generic Models
Type - Pset_QuantityTakeOff - Reference: n/a
Pset_BuildingElementProxyCommon - sets with these values: 2
Constraints - Level: Level: Level 1; Schedule Level: Level: Level 1; Elevation from Level: 1900 mm; Host: Dafa_ExFoil : Standard
Dimensions - Area: 0.119928 m2; Volume: 0.000142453 m3
Other - Family: Dafa_Hi-tack_Pipe_Collar_FaceBased: Type 345; Family and Type: Dafa_Hi-tack_Pipe_Collar_FaceBased: Type 345; Type: Dafa_Hi-tack_Pipe_Collar_FaceBased: Type 345; Type Id: Dafa_Hi-tack_Pipe_Collar_FaceBased: Type 345
Phasing - Phase Created: New Construction

# IfcBuildingElementProxy: Window Lining, Dafa_ExFoil_Lining_Foil 2 x double adhesive:Window Lining:279248
In: Level 1
Type - Material: DafaExFoilLiningFoil
Type - Constraints - Default Elevation: 0 mm
Type - Data - Foil Adhesive: DAFA foil adhesive; Vapor Barrier Tape: DAFA Hi-tack vapor barrier tape
Type - Dimensions - Thickness: 1 mm
Type - General - Revision: 1.0
Type - Green Building Properties - DGNB: Coming soon; EDP: Coming soon; EmiCode: Coming soon; Nordic Ecolabel: DAFA ExFoil lining foil is listed in the database for building products that can be used in Nordic Swan Ecolabelled buildings.
Type - Identity Data - Copyright: DAFA Building Solutions A/S; Description: With DAFA ExFoil lining foil, you are ensured an easy and secure installation of a vapor barrier at all 4 sides of openings/windows. This type of DAFA ExFoil lining foil is especially suitable for installation on new or existing vapor barriers, using two pre-installed sheets of double-sided tape.; Manufacturer: DAFA; Model: 250/410 mm x 50 m with 2 x double adhesive; Type Name: Window Lining; URL: https://DAFA-build.com/
Type - Other - Category: Generic Models; NominalWidth: 0 mm; AccessibilityPerformance: n/a; AssetIdentifier: n/a; AssetType: n/a; Author: DAFA Building Solutions A/S; BarCode: n/a; CodePerformance: n/a; Color: Transparent white w/ Lime green text; Constituents: n/a; DurationUnit: Year; ExpectedLife: n/a; Family Name: Dafa_ExFoil_Lining_Foil 2 x double adhesive; Features: Seals the opening all the way around, in one piece. DAFA ExFoil lining foil is fitted with butyl rubber and tape, which significantly facilitates the workflow; Finish: Nonwowen multilayer structure with reinforcing mesh; Grade: n/a; InstallationDate: To be filled by contractor; ManufacturerURL: https://DAFA-build.com; Material: Nonwowen multilayer structure with reinforcing mesh; ModelNumber: 620036876/620036582; ModelReference: DAFA AirStop System; NBSReference: n/a; NominalLength: 50000 mm; ProductInformation: https://DAFA-build.com/en/products/airstop/DAFA-exfoil-lining-foil; Reference: n/a; ReplacementCost: n/a; SerialNumber: n/a; Shape: Rectangular; Size: 250/410 mm x 50 m; TagNumber: n/a; WarrantyDescription: Depends on country.; WarrantyDurationLabor: To be filled by contractor; WarrantyDurationParts: Depends on country. Up to 30 years; WarrantyDurationUnit: Depends on country; WarrantyGuarantorLabor: To be filled by contractor; WarrantyGuarantorParts: To be filled by contractor; WarrantyStartDate: To be filled by contractor
Type - Pset_BuildingElementProxyCommon - Reference: n/a
Type - Pset_ElementShading - Color: Transparent white w/ Lime green text
Type - Pset_ManufacturerOccurrence - BarCode: n/a; SerialNumber: n/a
Type - Pset_ManufacturerTypeInformation - ModelReference: DAFA AirStop System; Manufacturer: DAFA
Type - Pset_PrecastConcreteElementGeneral - SerialNumber: n/a
Type - Pset_ProductRequirements - Category: Generic Models
Type - Pset_QuantityTakeOff - Reference: n/a
Pset_BuildingElementProxyCommon - sets with these values: 2
Constraints - Level: Level: Level 1; Elevation from Level: 0 mm; Moves With Nearby Elements: no; Offset from Host: 0 mm; Host: Level : Level 1
Dimensions - Area: 0.471656 m2; Depth: 120 mm; Height: 1200 mm; Volume: 0.00037776 m3; Width: 750 mm
Graphics - BottomOn: no
Materials and Finishes - ExFoilLining: DafaExFoilLiningFoil
Other - Family: Dafa_ExFoil_Lining_Foil 2 x double adhesive: Window Lining; Family and Type: Dafa_ExFoil_Lining_Foil 2 x double adhesive: Window Lining; Type: Dafa_ExFoil_Lining_Foil 2 x double adhesive: Window Lining; Type Id: Dafa_ExFoil_Lining_Foil 2 x double adhesive: Window Lining
Phasing - Phase Created: New Construction

# IfcBuildingElementProxy: Window Lining, Dafa_ExFoil_Lining_Foil double adhesive and butyl rubber:Window Lining:297119
In: Level 1
Type - Material: DafaExFoilLiningFoil
Type - Constraints - Default Elevation: 0 mm
Type - Data - Foil Adhesive: DAFA foil adhesive; Vapor Barrier Tape: DAFA Hi-tack vapor barrier tape
Type - Dimensions - Thickness: 1 mm
Type - General - Revision: 1.0
Type - Green Building Properties - DGNB: Coming soon; EDP: Coming soon; EmiCode: Coming soon; Nordic Ecolabel: DAFA ExFoil lining foil is listed in the database for building products that can be used in Nordic Swan Ecolabelled buildings.
Type - Identity Data - Copyright: DAFA Building Solutions A/S; Description: With DAFA ExFoil lining foil, you are ensured an easy and secure installation of a vapor barrier at all 4 sides of openings/windows. This type of DAFA ExFoil lining foil is preassembled with butyl rubber and tape, so that it works with rough surfaces such as concrete elements, aerated concrete and wood. Butyl rubber is extra strong and ensures good adhesion.; Manufacturer: DAFA; Model: 200/300/400 mm x 50 m with double adhesive and butyl; Type Name: Window Lining; URL: https://DAFA-build.com/
Type - Other - Category: Generic Models; NominalWidth: 0 mm; AccessibilityPerformance: n/a; AssetIdentifier: n/a; AssetType: n/a; Author: DAFA Building Solutions A/S; BarCode: n/a; CodePerformance: n/a; Color: Transparent white w/ Lime green text; Constituents: n/a; DurationUnit: Year; ExpectedLife: n/a; Family Name: Dafa_ExFoil_Lining_Foil double adhesive and butyl rubber; Features: Seals the opening all the way around, in one piece. DAFA ExFoil lining foil is fitted with butyl rubber and tape, which significantly facilitates the workflow; Finish: Nonwowen multilayer structure with reinforcing mesh; Grade: n/a; InstallationDate: To be filled by contractor; ManufacturerURL: https://DAFA-build.com; Material: Nonwowen multilayer structure with reinforcing mesh; ModelNumber: 620036874/620036875/620036584; ModelReference: DAFA AirStop System; NBSReference: n/a; NominalLength: 50000 mm; ProductInformation: https://DAFA-build.com/en/products/airstop/DAFA-exfoil-lining-foil; Reference: n/a; ReplacementCost: n/a; SerialNumber: n/a; Shape: Rectangular; Size: 200/300/400 mm x 50 m; TagNumber: n/a; WarrantyDescription: Depends on country.; WarrantyDurationLabor: To be filled by contractor; WarrantyDurationParts: Depends on country. Up to 30 years; WarrantyDurationUnit: Depends on country; WarrantyGuarantorLabor: To be filled by contractor; WarrantyGuarantorParts: To be filled by contractor; WarrantyStartDate: To be filled by contractor
Type - Pset_BuildingElementProxyCommon - Reference: n/a
Type - Pset_ElementShading - Color: Transparent white w/ Lime green text
Type - Pset_ManufacturerOccurrence - BarCode: n/a; SerialNumber: n/a
Type - Pset_ManufacturerTypeInformation - ModelReference: DAFA AirStop System; Manufacturer: DAFA
Type - Pset_PrecastConcreteElementGeneral - SerialNumber: n/a
Type - Pset_ProductRequirements - Category: Generic Models
Type - Pset_QuantityTakeOff - Reference: n/a
Pset_BuildingElementProxyCommon - sets with these values: 2
Constraints - Level: Level: Level 1; Elevation from Level: 0 mm; Moves With Nearby Elements: no; Offset from Host: 0 mm; Host: Level : Level 1
Dimensions - Area: 0.471656 m2; Depth: 120 mm; Height: 1200 mm; Volume: 0.00037776 m3; Width: 750 mm
Graphics - BottomOn: no
Materials and Finishes - ExFoilLining: DafaExFoilLiningFoil
Other - Family: Dafa_ExFoil_Lining_Foil double adhesive and butyl rubber: Window Lining; Family and Type: Dafa_ExFoil_Lining_Foil double adhesive and butyl rubber: Window Lining; Type: Dafa_ExFoil_Lining_Foil double adhesive and butyl rubber: Window Lining; Type Id: Dafa_ExFoil_Lining_Foil double adhesive and butyl rubber: Window Lining
Phasing - Phase Created: New Construction

# IfcBuildingElementProxy: Window Lining, Dafa_ExFoil_Lining_Foil 2 x double adhesive-WallBased:Window Lining:235330
In: Level 1
Type - Material: DafaExFoilLiningFoil
Type - Constraints(Type) - Default Elevation: 0 mm
Type - Data(Type) - Foil Adhesive: DAFA foil adhesive; Vapor Barrier Tape: DAFA Hi-tack vapor barrier tape
Type - Dimensions(Type) - Area: 0.48 m2; Depth: 120 mm; Height: 1500 mm; Width: 1000 mm
Type - General(Type) - Revision: 1.0
Type - Graphics(Type) - BottomOn: no
Type - Green Building Properties(Type) - DGNB: Coming soon; EDP: Coming soon; EmiCode: Coming soon; Nordic Ecolabel: DAFA ExFoil lining foil is listed in the database for building products that can be used in Nordic Swan Ecolabelled buildings.
Type - Identity Data(Type) - Copyright: DAFA Building Solutions A/S; Description: With DAFA ExFoil lining foil, you are ensured an easy and secure installation of a vapor barrier at all 4 sides of openings/windows. This type of DAFA ExFoil lining foil is especially suitable for installation on new or existing vapor barriers, using two pre-installed sheets of double-sided tape.; Manufacturer: DAFA; Model: 250/410 mm x 50 m with 2 x double adhesive; Type Name: Window Lining; URL: https://DAFA-build.com/
Type - Other(Type) - Category: Generic Models; AccessibilityPerformance: n/a; AssetIdentifier: n/a; AssetType: n/a; Author: DAFA Building Solutions A/S; BarCode: n/a; CodePerformance: n/a; Color: Transparent white w/ Lime green text; Constituents: n/a; DurationUnit: Year; ExpectedLife: n/a; Family Name: Dafa_ExFoil_Lining_Foil 2 x double adhesive-WallBased; Features: Seals the opening all the way around, in one piece. DAFA ExFoil lining foil is fitted with butyl rubber and tape, which significantly facilitates the workflow; Finish: Nonwowen multilayer structure with reinforcing mesh; Grade: n/a; InstallationDate: To be filled by contractor; ManufacturerURL: https://DAFA-build.com; Material: Nonwowen multilayer structure with reinforcing mesh; ModelNumber: 620036876/620036582; ModelReference: DAFA AirStop System; NBSReference: n/a; NominalLength: 50000 mm; NominalWidth: 0 mm; ProductInformation: https://DAFA-build.com/en/products/airstop/DAFA-exfoil-lining-foil; Reference: n/a; ReplacementCost: n/a; SerialNumber: n/a; Shape: Rectangular; Size: 250/410 mm x 50 m; TagNumber: n/a; WarrantyDescription: Depends on country.; WarrantyDurationLabor: To be filled by contractor; WarrantyDurationParts: Depends on country. Up to 30 years; WarrantyDurationUnit: Depends on country; WarrantyGuarantorLabor: To be filled by contractor; WarrantyGuarantorParts: To be filled by contractor; WarrantyStartDate: To be filled by contractor
Type - Pset_BuildingElementProxyCommon - Reference: n/a
Type - Pset_ElementShading - Color: Transparent white w/ Lime green text
Type - Pset_ManufacturerOccurrence - BarCode: n/a; SerialNumber: n/a
Type - Pset_ManufacturerTypeInformation - ModelReference: DAFA AirStop System; Manufacturer: DAFA
Type - Pset_PrecastConcreteElementGeneral - SerialNumber: n/a
Type - Pset_ProductRequirements - Category: Generic Models
Type - Pset_QuantityTakeOff - Reference: n/a
Pset_BuildingElementProxyCommon - sets with these values: 2
Constraints - Level: Level: Level 1; Elevation from Level: 900 mm
Dimensions - Area: 0.604756 m2; OffsetInWall: 25 mm; Volume: 0.00047976 m3
Other - Category: Generic Models; Family: Dafa_ExFoil_Lining_Foil 2 x double adhesive-WallBased: Window Lining; Family and Type: Dafa_ExFoil_Lining_Foil 2 x double adhesive-WallBased: Window Lining; Host Id: Basic Wall: Exterior - Brick on Mtl. Stud; Type: Dafa_ExFoil_Lining_Foil 2 x double adhesive-WallBased: Window Lining; Type Id: Dafa_ExFoil_Lining_Foil 2 x double adhesive-WallBased: Window Lining
Phasing - Phase Created: New Construction

# IfcBuildingElementProxy: Window Lining, Dafa_ExFoil_Lining_Foil double adhesive and butyl rubber-WallBased:Window Lining:297190
In: Level 1
Type - Material: DafaExFoilLiningFoil
Type - Constraints(Type) - Default Elevation: 0 mm
Type - Data(Type) - Foil Adhesive: DAFA foil adhesive; Vapor Barrier Tape: DAFA Hi-tack vapor barrier tape
Type - Dimensions(Type) - Area: 0.48 m2; Depth: 120 mm; Height: 1500 mm; Width: 1000 mm
Type - General(Type) - Revision: 1.0
Type - Graphics(Type) - BottomOn: no
Type - Green Building Properties(Type) - DGNB: Coming soon; EDP: Coming soon; EmiCode: Coming soon; Nordic Ecolabel: DAFA ExFoil lining foil is listed in the database for building products that can be used in Nordic Swan Ecolabelled buildings.
Type - Identity Data(Type) - Copyright: DAFA Building Solutions A/S; Description: With DAFA ExFoil lining foil, you are ensured an easy and secure installation of a vapor barrier at all 4 sides of openings/windows. This type of DAFA ExFoil lining foil is preassembled with butyl rubber and tape, so that it works with rough surfaces such as concrete elements, aerated concrete and wood. Butyl rubber is extra strong and ensures good adhesion.; Manufacturer: DAFA; Model: 200/300/400 mm x 50 m with double adhesive and butyl; Type Name: Window Lining; URL: https://DAFA-build.com/
Type - Other(Type) - Category: Generic Models; NominalWidth: 0 mm; AccessibilityPerformance: n/a; AssetIdentifier: n/a; AssetType: n/a; Author: DAFA Building Solutions A/S; BarCode: n/a; CodePerformance: n/a; Color: Transparent white w/ Lime green text; Constituents: n/a; DurationUnit: Year; ExpectedLife: n/a; Family Name: Dafa_ExFoil_Lining_Foil double adhesive and butyl rubber-WallBased; Features: Seals the opening all the way around, in one piece. DAFA ExFoil lining foil is fitted with butyl rubber and tape, which significantly facilitates the workflow; Finish: Nonwowen multilayer structure with reinforcing mesh; Grade: n/a; InstallationDate: To be filled by contractor; ManufacturerURL: https://DAFA-build.com; Material: Nonwowen multilayer structure with reinforcing mesh; ModelNumber: 620036874/620036875/620036584; ModelReference: DAFA AirStop System; NBSReference: n/a; NominalLength: 50000 mm; ProductInformation: https://DAFA-build.com/en/products/airstop/DAFA-exfoil-lining-foil; Reference: n/a; ReplacementCost: n/a; SerialNumber: n/a; Shape: Rectangular; Size: 200/300/400 mm x 50 m; TagNumber: n/a; WarrantyDescription: Depends on country.; WarrantyDurationLabor: To be filled by contractor; WarrantyDurationParts: Depends on country. Up to 30 years; WarrantyDurationUnit: Depends on country; WarrantyGuarantorLabor: To be filled by contractor; WarrantyGuarantorParts: To be filled by contractor; WarrantyStartDate: To be filled by contractor
Type - Pset_BuildingElementProxyCommon - Reference: n/a
Type - Pset_ElementShading - Color: Transparent white w/ Lime green text
Type - Pset_ManufacturerOccurrence - BarCode: n/a; SerialNumber: n/a
Type - Pset_ManufacturerTypeInformation - ModelReference: DAFA AirStop System; Manufacturer: DAFA
Type - Pset_PrecastConcreteElementGeneral - SerialNumber: n/a
Type - Pset_ProductRequirements - Category: Generic Models
Type - Pset_QuantityTakeOff - Reference: n/a
Pset_BuildingElementProxyCommon - sets with these values: 2
Constraints - Level: Level: Level 1; Elevation from Level: 900 mm
Dimensions - Area: 0.604756 m2; OffsetInWall: 25 mm; Volume: 0.00047976 m3
Other - Category: Generic Models; Host Id: Basic Wall: Exterior - Brick on Mtl. Stud; Family: Dafa_ExFoil_Lining_Foil double adhesive and butyl rubber-WallBased: Window Lining; Family and Type: Dafa_ExFoil_Lining_Foil double adhesive and butyl rubber-WallBased: Window Lining; Type: Dafa_ExFoil_Lining_Foil double adhesive and butyl rubber-WallBased: Window Lining; Type Id: Dafa_ExFoil_Lining_Foil double adhesive and butyl rubber-WallBased: Window Lining
Phasing - Phase Created: New Construction

# IfcDoor: 0910 x 2100mm (2)
In: Level 1
Type - OperationType: SINGLE_SWING_RIGHT; ParameterTakesPrecedence: no; Sizeable: no; Material: Door - Frame, Door - Panel
Type - M_Single-Flush:0910 x 2100mm:248460 - PanelOperation: SWINGING
Type - Analytical Properties - Define Thermal Properties by: Schematic Type; Analytic Construction: <None>
Type - Construction - Wall Closure: By host; Function: Interior
Type - Dimensions - Height: 2100 mm; Thickness: 51 mm; Trim Projection Ext: 25 mm; Trim Projection Int: 25 mm; Trim Width: 76 mm; Width: 910 mm
Type - Identity Data - OmniClass Number: 23.30.10.00; OmniClass Title: Doors; Type Mark: 15; Type Name: 0910 x 2100mm
Type - Materials and Finishes - Door Material: Door - Panel; Frame Material: Door - Frame
Type - Other - Category: Doors; Family Name: M_Single-Flush
OverallHeight: 2100 mm; OverallWidth: 910 mm
Pset_DoorCommon - IsExternal: no; Reference: 0910 x 2100mm
Pset_ProductRequirements - Category: Doors
Pset_QuantityTakeOff - Reference: 0910 x 2100mm
BaseQuantities - Height: 2100 mm; Width: 910 mm; Area: 3.13123 m2
Constraints - Level: Level: Level 1; Sill Height: 0 mm
Dimensions - Area: 3.13123 m2; Volume: 0.117457 m3
Other - Host Id: Basic Wall: Exterior - Brick on Mtl. Stud; Family: M_Single-Flush: 0910 x 2100mm; Family and Type: M_Single-Flush: 0910 x 2100mm; Head Height: 2100 mm; Type: M_Single-Flush: 0910 x 2100mm; Type Id: M_Single-Flush: 0910 x 2100mm
Phasing - Phase Created: New Construction
Name (M_Single-Flush:0910 x 2100mm:...) | Mark
248460 | 1
297192 | 2

# IfcOpeningElement: Opening (8)
In: Level 1
BaseQuantities - Depth: 350 mm
Name | Height (mm) | Width (mm)
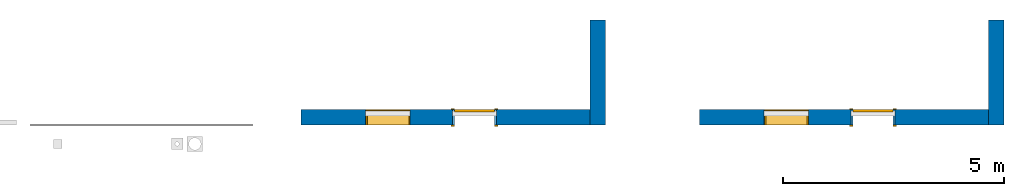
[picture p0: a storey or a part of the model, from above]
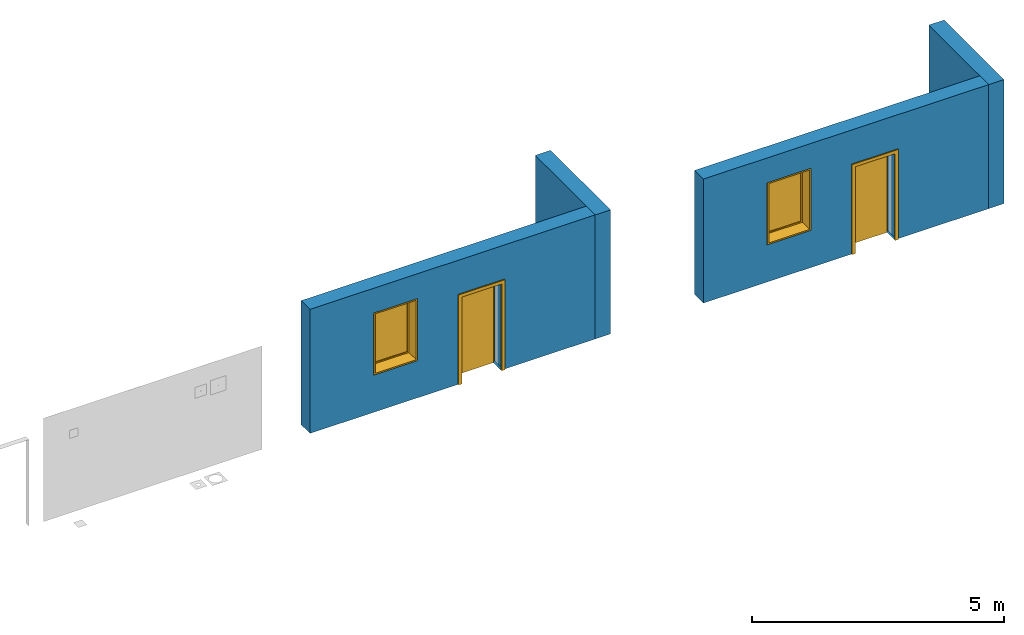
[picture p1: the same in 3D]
Properties of the parts of a building model (IFC2X3), part 2 of 2

# IfcOpeningElement: Opening (8)
Name | Height (mm) | Width (mm)
Basic Wall:Exterior - Brick on Mtl. Stud:207076 | 1000 | 1500 | Constraints - Elevation from Level: 900 mm; Level: Level: Level 1; Dimensions - Area: 0.604756 m2; OffsetInWall: 25 mm; Volume: 0.00047976 m3; Other - Category: Generic Models; Family: Dafa_ExFoil_Lining_Foil 2 x double adhesive-WallBased: Window Lining; Family and Type: Dafa_ExFoil_Lining_Foil 2 x double adhesive-WallBased: Window Lining; Host Id: Basic Wall: Exterior - Brick on Mtl. Stud; Type: Dafa_ExFoil_Lining_Foil 2 x double adhesive-WallBased: Window Lining; Type Id: Dafa_ExFoil_Lining_Foil 2 x double adhesive-WallBased: Window Lining; Phasing - Phase Created: New Construction; Pset_ElementShading - Roughness: 304.8 mm; Pset_ProductRequirements - Category: Walls; Pset_QuantityTakeOff - Reference: Exterior - Brick on Mtl. Stud; sets with these values: 2
Basic Wall:Exterior - Brick on Mtl. Stud:207076 | 1000 | 2100 | Constraints - Elevation from Level: 0.708015 mm; Level: Level: Level 1; Dimensions - Area: 0.749956 m2; OffsetInWall: 25 mm; Volume: 0.00062376 m3; Other - Category: Generic Models; Family: Dafa_ExFoil_Lining_Foil 2 x double adhesive-WallBased: Door Lining; Family and Type: Dafa_ExFoil_Lining_Foil 2 x double adhesive-WallBased: Door Lining; Host Id: Basic Wall: Exterior - Brick on Mtl. Stud; Type: Dafa_ExFoil_Lining_Foil 2 x double adhesive-WallBased: Door Lining; Type Id: Dafa_ExFoil_Lining_Foil 2 x double adhesive-WallBased: Door Lining; Phasing - Phase Created: New Construction; Pset_ElementShading - Roughness: 304.8 mm; Pset_ProductRequirements - Category: Walls; Pset_QuantityTakeOff - Reference: Exterior - Brick on Mtl. Stud; sets with these values: 2
M_Single-Flush:0910 x 2100mm:297192:1 | 910 | 2100
Basic Wall:Exterior - Brick on Mtl. Stud:297188 | 1000 | 1500 | Constraints - Elevation from Level: 900 mm; Level: Level: Level 1; Dimensions - Area: 0.604756 m2; OffsetInWall: 25 mm; Volume: 0.00047976 m3; Other - Category: Generic Models; Family: Dafa_ExFoil_Lining_Foil double adhesive and butyl rubber-WallBased: Window Lining; Family and Type: Dafa_ExFoil_Lining_Foil double adhesive and butyl rubber-WallBased: Window Lining; Host Id: Basic Wall: Exterior - Brick on Mtl. Stud; Type: Dafa_ExFoil_Lining_Foil double adhesive and butyl rubber-WallBased: Window Lining; Type Id: Dafa_ExFoil_Lining_Foil double adhesive and butyl rubber-WallBased: Window Lining; Phasing - Phase Created: New Construction; Pset_ElementShading - Roughness: 304.8 mm; Pset_ProductRequirements - Category: Walls; Pset_QuantityTakeOff - Reference: Exterior - Brick on Mtl. Stud; sets with these values: 2
Basic Wall:Exterior - Brick on Mtl. Stud:297188 | 1000 | 2100 | Constraints - Elevation from Level: 0.708015 mm; Level: Level: Level 1; Dimensions - Area: 0.749956 m2; OffsetInWall: 25 mm; Volume: 0.00062376 m3; Other - Category: Generic Models; Family: Dafa_ExFoil_Lining_Foil double adhesive and butyl rubber-WallBased: Door Lining; Family and Type: Dafa_ExFoil_Lining_Foil double adhesive and butyl rubber-WallBased: Door Lining; Host Id: Basic Wall: Exterior - Brick on Mtl. Stud; Type: Dafa_ExFoil_Lining_Foil double adhesive and butyl rubber-WallBased: Door Lining; Type Id: Dafa_ExFoil_Lining_Foil double adhesive and butyl rubber-WallBased: Door Lining; Phasing - Phase Created: New Construction; Pset_ElementShading - Roughness: 304.8 mm; Pset_ProductRequirements - Category: Walls; Pset_QuantityTakeOff - Reference: Exterior - Brick on Mtl. Stud; sets with these values: 2
M_Fixed:1500 x 1000 mm:215948:1 | 1000 | 1500
M_Single-Flush:0910 x 2100mm:248460:1 | 910 | 2100
M_Fixed:1500 x 1000 mm:297189:1 | 1000 | 1500

# IfcWallStandardCase: Basic Wall:Exterior - Brick on Mtl. Stud (4)
In: Level 1
Type - PredefinedType: STANDARD; Material: Brick, Common 90 mm, Air 76 mm, Plywood, Sheathing 19 mm, Metal Stud Layer 152 mm, Gypsum Wall Board (1) 13 mm
Type - Analytical Properties - Absorptance: 0.1; Heat Transfer Coefficient (U): 0.105419; Roughness: 1; Thermal mass: 144360; Thermal Resistance (R): 9.48591
Type - Construction - Function: Exterior; Width: 350 mm; Wrapping at Inserts: Do not wrap
Type - Graphics - Coarse Scale Fill Color: 0
Type - Identity Data - Type Name: Exterior - Brick on Mtl. Stud
Type - Materials and Finishes - Structural Material: Metal Stud Layer
Type - Other - Category: Walls; Family Name: Basic Wall
Type - Pset_ElementShading - Roughness: 304.8 mm
Type - Pset_ProductRequirements - Category: Walls
Type - Pset_QuantityTakeOff - Reference: Exterior - Brick on Mtl. Stud
Type - Pset_ReinforcementBarPitchOfWall - Reference: Exterior - Brick on Mtl. Stud
Type - Pset_WallCommon - Reference: Exterior - Brick on Mtl. Stud; ThermalTransmittance: 0.105419 kg/K/s3; IsExternal: no
BaseQuantities - Height: 3000 mm; Width: 350 mm
Constraints - Base Constraint: Level: Level 1; Base Extension Distance: 0 mm; Base is Attached: no; Base Offset: 0 mm; Location Line: Wall Centerline; Related to Mass: no; Room Bounding: yes; Top Extension Distance: 0 mm; Top is Attached: no; Top Offset: 0 mm; Unconnected Height: 3000 mm
Other - Family: Basic Wall: Exterior - Brick on Mtl. Stud; Family and Type: Basic Wall: Exterior - Brick on Mtl. Stud; Type: Basic Wall: Exterior - Brick on Mtl. Stud; Type Id: Basic Wall: Exterior - Brick on Mtl. Stud
Phasing - Phase Created: New Construction
Structural - Enable Analytical Model: no; Structural: no; Structural Usage: Non-bearing
Pset_QuantityTakeOff - sets with these values: 2
Pset_WallCommon - IsExternal: yes; ExtendToStructure: no; LoadBearing: no
Name (Basic Wall:Exterior - Brick on Mtl. Stud:...) | BaseQuantities, Length (mm) | GrossFootprintArea (m2) | NetVolume (m3) | NetSideArea (m2) | Area (m2) | Dimensions, Length (mm) | Volume (m3)
207076 | 6525 | 2.28375 | 6851250000 | 19575000 | 15.9669 | 6700 | 5.5884
252546 | 2375 | 0.83125 | 2493750000 | 7125000 | 7.125 | 2200 | 2.49375
297188 | 6525 | 2.28375 | 6851250000 | 19575000 | 15.9669 | 6700 | 5.5884
297193 | 2375 | 0.83125 | 2493750000 | 7125000 | 7.125 | 2200 | 2.49375

# IfcWindow: 1500 x 1000 mm (2)
In: Level 1
Type - ParameterTakesPrecedence: no; Sizeable: no; Material: Glass, Sash
Type - Analytical Properties - Analytic Construction: <None>; Define Thermal Properties by: Schematic Type
Type - Construction - Wall Closure: By host
Type - Dimensions - Default Sill Height: 800 mm; Height: 1500 mm; Width: 1000 mm; Window Inset: 19 mm
Type - Identity Data - OmniClass Number: 23.30.20.17.11; OmniClass Title: Fixed Windows; Type Mark: 15; Type Name: 1500 x 1000 mm
Type - Materials and Finishes - Frame Exterior Material: Sash; Frame Interior Material: Sash; Glass Pane Material: Glass; Sash: Sash
Type - Other - Category: Windows; Family Name: M_Fixed
OverallHeight: 1500 mm; OverallWidth: 1000 mm
Pset_ProductRequirements - Category: Windows
Pset_QuantityTakeOff - Reference: 1500 x 1000 mm
Pset_WindowCommon - IsExternal: yes; Reference: 1500 x 1000 mm
BaseQuantities - Height: 1500 mm; Width: 1000 mm; Area: 3.59692 m2
Constraints - Level: Level: Level 1; Sill Height: 900 mm
Dimensions - Area: 3.59692 m2; Volume: 0.074094 m3
Other - Host Id: Basic Wall: Exterior - Brick on Mtl. Stud; Family: M_Fixed: 1500 x 1000 mm; Family and Type: M_Fixed: 1500 x 1000 mm; Head Height: 2400 mm; Type: M_Fixed: 1500 x 1000 mm; Type Id: M_Fixed: 1500 x 1000 mm
Phasing - Phase Created: New Construction
Name (M_Fixed:1500 x 1000 mm:...) | Mark
215948 | 9
297189 | 12
